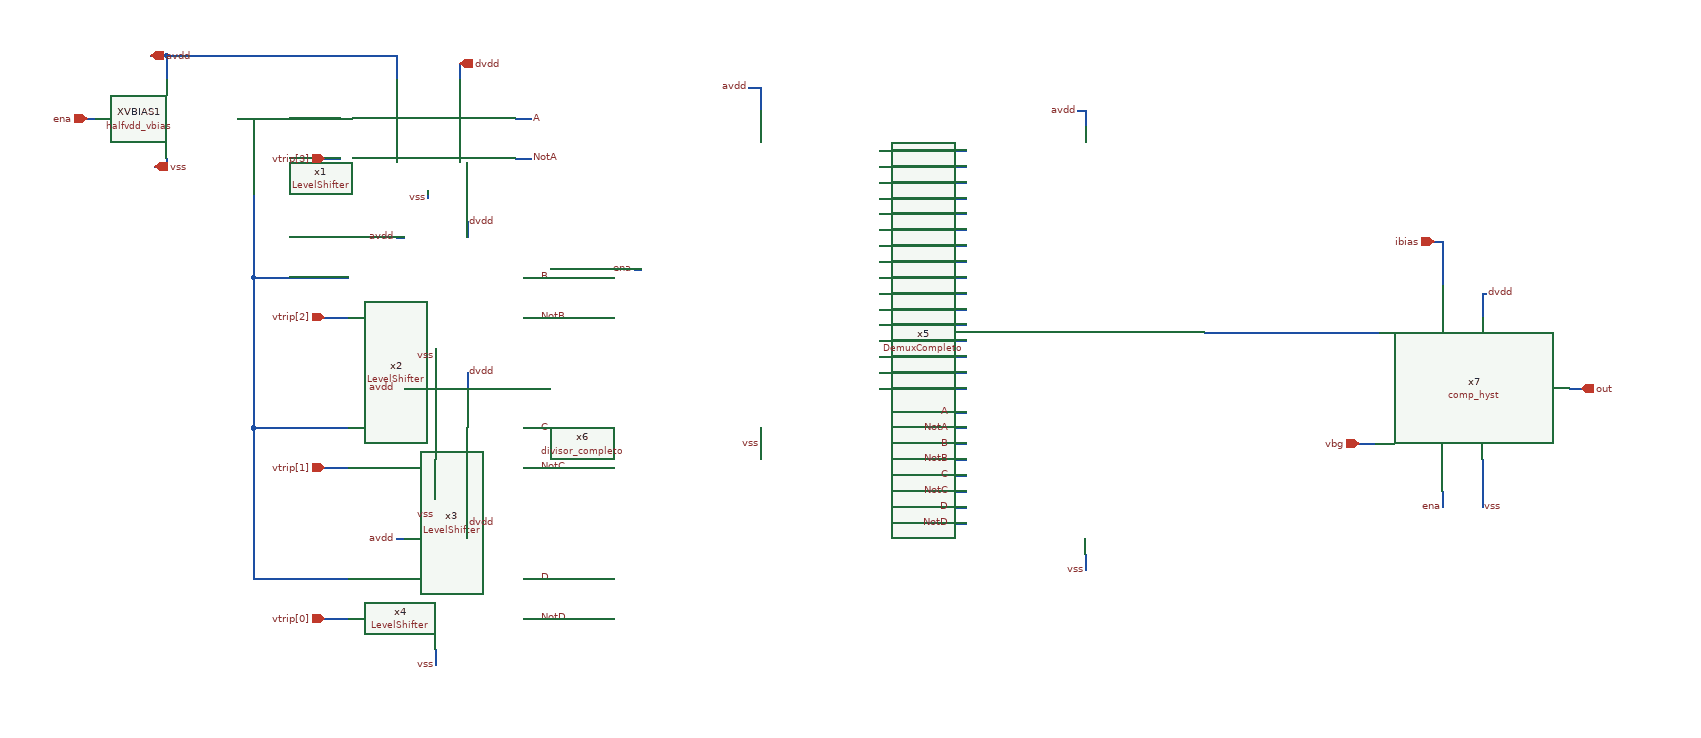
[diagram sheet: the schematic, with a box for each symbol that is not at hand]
v {xschem version=3.4.5 file_version=1.2
}
G {}
K {}
V {}
S {}
E {}
N 2225 -1075 2355 -1075 {
lab=#net1}
N 2035 -1075 2045 -1075 {
lab=ena}
N 2135 -1025 2135 -1015 {
lab=vss}
N 2245 -1075 2245 -875 {
lab=#net1}
N 2245 -875 2365 -875 {
lab=#net1}
N 2465 -985 2465 -975 {
lab=vss}
N 2245 -875 2245 -695 {
lab=#net1}
N 2245 -695 2245 -685 {
lab=#net1}
N 2245 -685 2365 -685 {
lab=#net1}
N 2245 -495 2365 -495 {
lab=#net1}
N 2245 -685 2245 -495 {
lab=#net1}
N 2335 -825 2365 -825 {
lab=vtrip[2]}
N 2335 -635 2365 -635 {
lab=vtrip[1]}
N 2335 -445 2365 -445 {
lab=vtrip[0]}
N 2425 -545 2435 -545 {
lab=avdd}
N 2425 -735 2435 -735 {
lab=avdd}
N 2425 -925 2435 -925 {
lab=avdd}
N 2425 -1155 2425 -1125 {
lab=avdd}
N 2325 -1155 2425 -1155 {
lab=avdd}
N 2505 -1145 2505 -1125 {
lab=dvdd}
N 2515 -945 2515 -925 {
lab=dvdd}
N 2515 -755 2515 -735 {
lab=dvdd}
N 2515 -565 2515 -545 {
lab=dvdd}
N 2475 -785 2475 -775 {
lab=vss}
N 2475 -595 2475 -585 {
lab=vss}
N 2475 -585 2475 -575 {
lab=vss}
N 2475 -405 2475 -395 {
lab=vss}
N 2475 -395 2475 -385 {
lab=vss}
N 2575 -1075 2595 -1075 {
lab=A}
N 2585 -1025 2595 -1025 {
lab=NotA}
N 2575 -1025 2585 -1025 {
lab=NotA}
N 2585 -875 2605 -875 {
lab=B}
N 2595 -825 2605 -825 {
lab=NotB}
N 2585 -825 2595 -825 {
lab=NotB}
N 2585 -685 2605 -685 {
lab=C}
N 2595 -635 2605 -635 {
lab=NotC}
N 2585 -635 2595 -635 {
lab=NotC}
N 2585 -495 2605 -495 {
lab=D}
N 2595 -445 2605 -445 {
lab=NotD}
N 2585 -445 2595 -445 {
lab=NotD}
N 3125 -705 3145 -705 {
lab=A}
N 3125 -685 3145 -685 {
lab=NotA}
N 3125 -665 3145 -665 {
lab=B}
N 3125 -645 3135 -645 {
lab=NotB}
N 3135 -645 3145 -645 {
lab=NotB}
N 3125 -625 3145 -625 {
lab=C}
N 3125 -605 3145 -605 {
lab=NotC}
N 3125 -585 3145 -585 {
lab=D}
N 3125 -565 3145 -565 {
lab=NotD}
N 3295 -525 3295 -505 {
lab=vss}
N 3295 -1085 3295 -1065 {
lab=avdd}
N 3285 -1085 3295 -1085 {
lab=avdd}
N 3445 -805 3485 -805 {
lab=#net2}
N 2885 -685 2885 -665 {
lab=vss}
N 2725 -885 2735 -885 {
lab=ena}
N 3040 -875 3050 -875 {
lab=#net3}
N 3035 -875 3040 -875 {
lab=#net3}
N 3080 -875 3145 -875 {
lab=#net3}
N 3050 -875 3080 -875 {
lab=#net3}
N 3035 -1035 3145 -1035 {
lab=#net4}
N 3035 -1015 3145 -1015 {
lab=#net5}
N 3035 -995 3145 -995 {
lab=#net6}
N 3035 -975 3145 -975 {
lab=#net7}
N 3035 -955 3145 -955 {
lab=#net8}
N 3035 -935 3145 -935 {
lab=#net9}
N 3035 -915 3145 -915 {
lab=#net10}
N 3035 -895 3145 -895 {
lab=#net11}
N 3035 -855 3145 -855 {
lab=#net12}
N 3035 -835 3145 -835 {
lab=#net13}
N 3035 -815 3145 -815 {
lab=#net14}
N 3035 -795 3145 -795 {
lab=#net15}
N 3035 -775 3145 -775 {
lab=#net16}
N 3035 -755 3145 -755 {
lab=#net17}
N 3035 -735 3145 -735 {
lab=#net18}
N 2870 -1115 2885 -1115 {
lab=avdd}
N 2885 -1115 2885 -1085 {
lab=avdd}
N 2115 -1155 2135 -1155 {
lab=avdd}
N 2135 -1155 2135 -1125 {
lab=avdd}
N 2135 -1155 2325 -1155 {
lab=avdd}
N 3485 -805 3545 -805 {
lab=#net2}
N 3545 -805 3665 -805 {
lab=#net2}
N 3905 -735 3920 -735 {
lab=out}
N 3640 -665 3660 -665 {
lab=vbg}
N 3745 -885 3745 -865 {
lab=ibias}
N 3795 -855 3800 -855 {
lab=dvdd}
N 3795 -855 3795 -825 {
lab=dvdd}
N 3745 -605 3745 -585 {
lab=ena}
N 3795 -645 3795 -585 {
lab=vss}
N 2120 -1015 2135 -1015 {
lab=vss}
N 2335 -1025 2355 -1025 {
lab=vtrip[3]}
N 3735 -920 3745 -920 {
lab=ibias}
N 3745 -920 3745 -885 {
lab=ibias}
C {LevelShifter.sym} 2315 -945 0 0 {name=x1}
C {halfvdd_vbias.sym} 2015 -1015 0 0 {name=XVBIAS1}
C {LevelShifter.sym} 2325 -745 0 0 {name=x2}
C {LevelShifter.sym} 2325 -555 0 0 {name=x3}
C {LevelShifter.sym} 2325 -365 0 0 {name=x4}
C {devices/lab_pin.sym} 2425 -925 0 0 {name=p11 sig_type=std_logic lab=avdd}
C {devices/lab_pin.sym} 2425 -735 0 0 {name=p12 sig_type=std_logic lab=avdd}
C {devices/lab_pin.sym} 2425 -545 0 0 {name=p13 sig_type=std_logic lab=avdd}
C {devices/lab_pin.sym} 2515 -945 0 1 {name=p14 sig_type=std_logic lab=dvdd}
C {devices/lab_pin.sym} 2515 -755 0 1 {name=p15 sig_type=std_logic lab=dvdd}
C {devices/lab_pin.sym} 2515 -565 0 1 {name=p16 sig_type=std_logic lab=dvdd}
C {devices/lab_pin.sym} 2595 -1075 0 1 {name=p17 sig_type=std_logic lab=A}
C {devices/lab_pin.sym} 2595 -1025 0 1 {name=p18 sig_type=std_logic lab=NotA}
C {devices/lab_pin.sym} 2605 -875 0 1 {name=p19 sig_type=std_logic lab=B}
C {devices/lab_pin.sym} 2605 -825 0 1 {name=p20 sig_type=std_logic lab=NotB}
C {devices/lab_pin.sym} 2605 -685 0 1 {name=p21 sig_type=std_logic lab=C}
C {devices/lab_pin.sym} 2605 -635 0 1 {name=p22 sig_type=std_logic lab=NotC}
C {devices/lab_pin.sym} 2605 -495 0 1 {name=p23 sig_type=std_logic lab=D}
C {devices/lab_pin.sym} 2605 -445 0 1 {name=p24 sig_type=std_logic lab=NotD}
C {DemuxCompleto.sym} 3295 -805 0 0 {name=x5}
C {devices/lab_pin.sym} 3125 -705 0 0 {name=p25 sig_type=std_logic lab=A}
C {devices/lab_pin.sym} 3125 -685 0 0 {name=p26 sig_type=std_logic lab=NotA}
C {devices/lab_pin.sym} 3125 -665 0 0 {name=p27 sig_type=std_logic lab=B}
C {devices/lab_pin.sym} 3125 -645 0 0 {name=p28 sig_type=std_logic lab=NotB}
C {devices/lab_pin.sym} 3125 -625 0 0 {name=p29 sig_type=std_logic lab=C}
C {devices/lab_pin.sym} 3125 -605 0 0 {name=p30 sig_type=std_logic lab=NotC}
C {devices/lab_pin.sym} 3125 -585 0 0 {name=p31 sig_type=std_logic lab=D}
C {devices/lab_pin.sym} 3125 -565 0 0 {name=p32 sig_type=std_logic lab=NotD}
C {devices/lab_pin.sym} 3285 -1085 0 0 {name=p33 sig_type=std_logic lab=avdd}
C {devices/lab_pin.sym} 2870 -1115 0 0 {name=p35 sig_type=std_logic lab=avdd}
C {devices/lab_pin.sym} 2725 -885 0 0 {name=p37 sig_type=std_logic lab=ena}
C {divisor_completo.sym} 2495 -645 0 0 {name=x6}
C {comp_hyst.sym} 3755 -725 0 0 {name=x7}
C {devices/lab_pin.sym} 3800 -855 0 1 {name=p42 sig_type=std_logic lab=dvdd}
C {devices/iopin.sym} 2115 -1155 0 1 {name=p1 lab=avdd}
C {devices/iopin.sym} 2505 -1145 0 1 {name=p2 lab=dvdd}
C {devices/ipin.sym} 2035 -1075 0 0 {name=p3 lab=ena}
C {devices/lab_pin.sym} 3745 -585 0 0 {name=p4 sig_type=std_logic lab=ena}
C {devices/iopin.sym} 2120 -1015 0 1 {name=p6 lab=vss}
C {devices/lab_pin.sym} 2465 -975 0 0 {name=p7 sig_type=std_logic lab=vss}
C {devices/lab_pin.sym} 2475 -775 0 0 {name=p34 sig_type=std_logic lab=vss}
C {devices/lab_pin.sym} 2475 -575 0 0 {name=p38 sig_type=std_logic lab=vss}
C {devices/lab_pin.sym} 2475 -385 0 0 {name=p44 sig_type=std_logic lab=vss}
C {devices/lab_pin.sym} 2885 -665 0 0 {name=p45 sig_type=std_logic lab=vss}
C {devices/lab_pin.sym} 3295 -505 0 0 {name=p46 sig_type=std_logic lab=vss}
C {devices/lab_pin.sym} 3795 -585 0 1 {name=p47 sig_type=std_logic lab=vss}
C {devices/ipin.sym} 2335 -1025 0 0 {name=p10 lab=vtrip[3]}
C {devices/opin.sym} 3920 -735 0 0 {name=p36 lab=out}
C {devices/ipin.sym} 3640 -665 0 0 {name=p41 lab=vbg}
C {devices/ipin.sym} 2335 -825 0 0 {name=p5 lab=vtrip[2]}
C {devices/ipin.sym} 2335 -635 0 0 {name=p8 lab=vtrip[1]}
C {devices/ipin.sym} 2335 -445 0 0 {name=p9 lab=vtrip[0]}
C {devices/ipin.sym} 3735 -920 0 0 {name=p39 lab=ibias}
